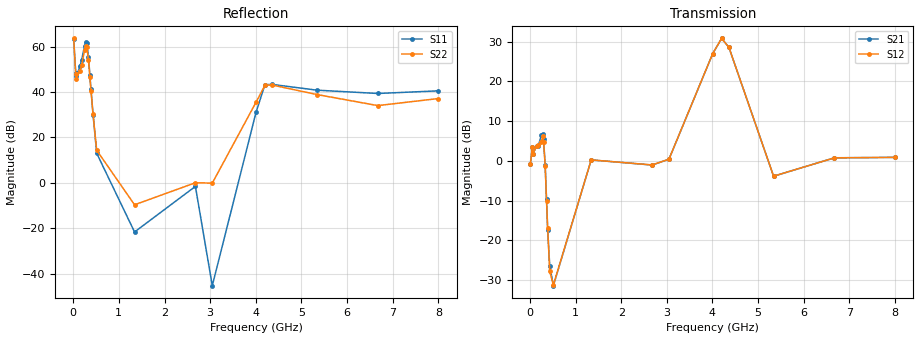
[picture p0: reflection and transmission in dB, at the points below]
!Agilent Technologies,N5230A,US43500312,A.07.50.67
!Agilent N5230A: A.07.50.67
!Date: Tuesday, June 09, 2015 15:40:33
!Correction: S11(Full 2 Port(1,2))
!S21(Full 2 Port(1,2))
!S12(Full 2 Port(1,2))
!S22(Full 2 Port(1,2))
!S2P File: Measurements: S11, S21, S12, S22:
# Hz S  MA  R 50
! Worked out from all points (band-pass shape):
!   1601 points, 10 MHz to 8 GHz, reference 50 ohm
!   highest |S21| = 30.79 dB at 4.2 GHz (marker M1); lowest = -31.4 dB at 514.4 MHz (marker M2)
!   |S21| within 3 dB of the highest: 4.032 GHz to 4.391 GHz (358.3 MHz wide, 8.51 % of centre)
!   lowest |S11| = -45.4 dB at 3.046 GHz (marker M3), VSWR 1.01, Z = 49.5 - j0.222 ohm
!   |S11| at or under -10 dB: 971.2 MHz to 1.888 GHz (916.7 MHz wide, 64.1 % of centre); 2.033 GHz to 2.294 GHz (261 MHz wide, 12.1 % of centre); 2.972 GHz to 3.111 GHz (138.4 MHz wide, 4.55 % of centre)
!   |S22| runs from -15.7 to 63.6 dB; largest |S21 - S12| = 0.39
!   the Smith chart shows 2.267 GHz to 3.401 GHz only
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1e7  1488 171.1  0.9238 -39.5  0.9071 -57.4  1520 -19.4
5.494375e7  259.8 327.3  1.493 4.4  1.481 9.5  243.5 93.9
6.493125e7  219.6 339.0  1.236 7.8  1.227 6.6  198.2 98.2
1.49825e8  371.8 403.8  1.521 5.6  1.536 10.9  292.5 126.2
1.847812e8  512.6 412.4  1.555 4.7  1.559 5.1  396.4 129.3
2.497e8  1051 412.7  2.083 11.0  1.706 8.7  835.1 125.8
2.796625e8  1258 426.6  2.155 28.7  2.079 28.2  1022 140.2
2.996375e8  1176 435.5  1.854 41.9  1.745 35.3  973.2 150.6
3.345938e8  579.5 469.5  0.8904 87.3  0.8677 84.3  500.5 187.8
3.645562e8  238.4 479.6  0.3288 98.1  0.3113 86.1  214.7 203.0
3.89525e8  113.7 486.7  0.135 108.3  0.1428 109.8  106.3 215.5
4.344688e8  31.65 494.8  0.04779 97.8  0.04069 97.3  32.16 236.6
5.143688e8  4.469 516.6  0.02689 114.7  0.02747 114.9  5.198 291.3
1.343331e9  0.08236 781.1  1.027 161.2  1.027 161.2  0.327 783.7
2.676662e9  0.8322 685.9  0.8849 164.6  0.8875 164.7  1.001 1237.7
3.0462e9  0.005394 564.6  1.045 178.9  1.049 178.9  0.9812 1330.6
4.005e9  35.72 418.1  22.27 216.1  22.32 216.4  59.58 1533.9
4.199756e9  145.1 344.4  34.62 136.1  34.67 136.3  140.8 1489.8
4.359556e9  146.9 300.4  26.72 73.5  26.77 73.7  142.2 1453.9
5.338331e9  109.7 291.1  0.64 17.0  0.6409 17.4  87.9 1418.2
6.671662e9  92.79 310.4  1.092 25.3  1.09 26.0  50.16 1361.3
8e9  106 324.5  1.104 16.4  1.105 16.1  71.77 1320.6
